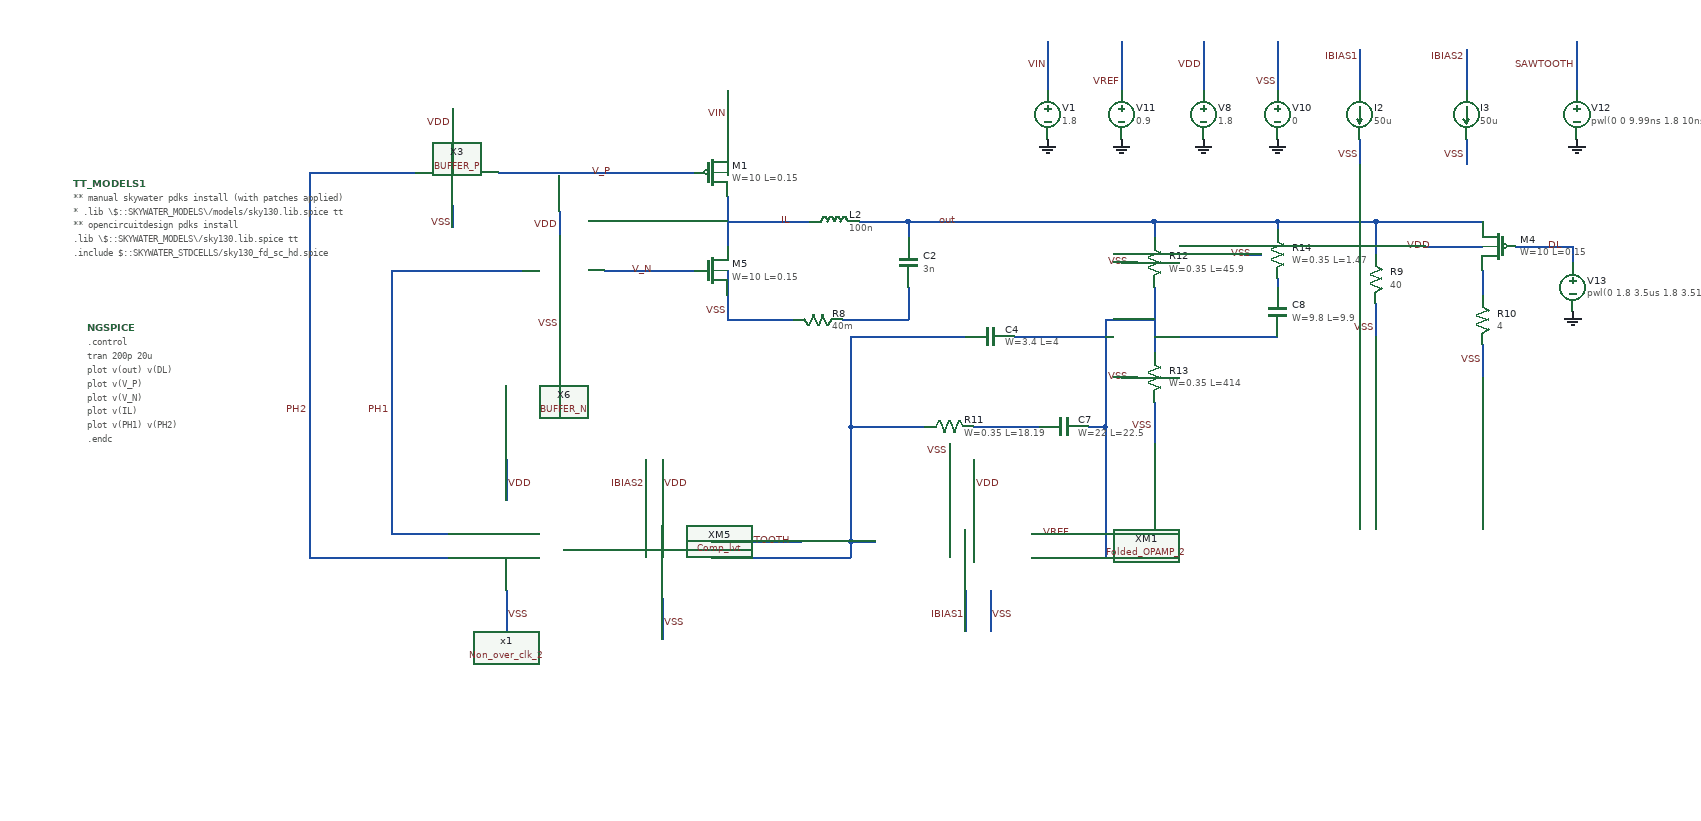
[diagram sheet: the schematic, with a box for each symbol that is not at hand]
v {xschem version=3.0.0 file_version=1.2 }
G {}
K {}
V {}
S {}
E {}
N 1650 880 1650 940 {
lab=IL}
N 1650 820 1650 850 {
lab=VIN}
N 1560 850 1610 850 {
lab=V_P}
N 1650 750 1650 820 {
lab=VIN}
N 1650 1000 1650 1030 {
lab=VSS}
N 1650 910 1710 910 {
lab=IL}
N 1710 910 1750 910 {
lab=IL}
N 1870 910 1870 930 {
lab=out}
N 1810 910 1870 910 {
lab=out}
N 1870 990 1870 1030 {
lab=#net1}
N 1870 910 1980 910 {
lab=out}
N 1950 1200 1950 1250 {
lab=VDD}
N 1970 1360 1970 1410 {
lab=VSS}
N 1940 1360 1940 1410 {
lab=IBIAS1}
N 2020 1320 2070 1320 {
lab=#net2}
N 2020 1290 2070 1290 {
lab=VREF}
N 2230 740 2230 750 {
lab=VDD}
N 2230 690 2230 740 {
lab=VDD}
N 2320 720 2320 740 {
lab=VSS}
N 2320 740 2320 750 {
lab=VSS}
N 2320 690 2320 720 {
lab=VSS}
N 2420 700 2420 760 {
lab=IBIAS1}
N 1570 1200 1570 1250 {
lab=VDD}
N 1570 1370 1570 1420 {
lab=VSS}
N 2130 720 2130 740 {
lab=VREF}
N 2130 740 2130 750 {
lab=VREF}
N 2130 690 2130 720 {
lab=VREF}
N 2070 1320 2100 1320 {
lab=#net2}
N 1550 1200 1550 1250 {
lab=IBIAS2}
N 2685 690 2685 750 {
lab=SAWTOOTH}
N 1370 850 1560 850 {
lab=V_P}
N 1980 910 2160 910 {
lab=out}
N 2170 910 2170 930 {
lab=out}
N 2170 990 2170 1040 {
lab=#net2}
N 2170 1130 2170 1180 {
lab=VSS}
N 1950 1160 2030 1160 {
lab=#net3}
N 1800 1160 1890 1160 {
lab=#net4}
N 1800 1160 1800 1300 {
lab=#net4}
N 2110 1160 2110 1290 {
lab=#net2}
N 2090 1160 2110 1160 {
lab=#net2}
N 1800 1050 1940 1050 {
lab=#net4}
N 2000 1050 2110 1050 {
lab=#net2}
N 2110 1090 2110 1160 {
lab=#net2}
N 1800 1300 1830 1300 {
lab=#net4}
N 2110 1290 2110 1320 {
lab=#net2}
N 2100 1320 2110 1320 {
lab=#net2}
N 2170 910 2320 910 {
lab=out}
N 2320 910 2320 920 {
lab=out}
N 2320 980 2320 990 {
lab=#net5}
N 2160 910 2170 910 {
lab=out}
N 2110 1030 2110 1090 {
lab=#net2}
N 2110 1030 2170 1030 {
lab=#net2}
N 2170 1040 2170 1070 {
lab=#net2}
N 2440 910 2440 950 {
lab=out}
N 2320 910 2440 910 {
lab=out}
N 2440 1010 2440 1050 {
lab=VSS}
N 1630 1320 1800 1320 {
lab=#net4}
N 1800 1300 1800 1320 {
lab=#net4}
N 1560 970 1610 970 {
lab=V_N}
N 1650 970 1650 1000 {
lab=VSS}
N 2440 910 2570 910 {
lab=out}
N 2570 1060 2570 1100 {
lab=VSS}
N 2570 970 2570 1000 {
lab=#net6}
N 2610 940 2680 940 {
lab=DL}
N 2680 940 2680 960 {
lab=DL}
N 1380 1200 1380 1250 {
lab=VDD}
N 1380 1360 1380 1410 {
lab=VSS}
N 1140 850 1270 850 {
lab=PH2}
N 1140 850 1140 1290 {
lab=PH2}
N 1315 890 1315 917.5 {
lab=VSS}
N 1315 772.5 1315 807.5 {
lab=VDD}
N 1500 970 1560 970 {
lab=V_N}
N 1240 970 1400 970 {
lab=PH1}
N 1240 970 1240 1060 {
lab=PH1}
N 1445 1010 1445 1047.5 {
lab=VSS}
N 1445 897.5 1445 927.5 {
lab=VDD}
N 1240 1290 1300 1290 {
lab=PH1}
N 1240 1060 1240 1290 {
lab=PH1}
N 1140 1320 1300 1320 {
lab=PH2}
N 1140 1290 1140 1320 {
lab=PH2}
N 1800 1050 1800 1160 {
lab=#net4}
N 2170 1050 2220 1050 {
lab=#net2}
N 2220 1050 2320 1050 {
lab=#net2}
N 1970 1360 1970 1410 {
lab=VSS}
N 2510 940 2570 940 {
lab=VDD}
N 1630 1300 1740 1300 {
lab=SAWTOOTH}
N 1920 1180 1920 1200 {
lab=VSS}
N 2280 950 2300 950 {
lab=VSS}
N 2130 960 2150 960 {
lab=VSS}
N 2130 1100 2150 1100 {
lab=VSS}
N 1840 1030 1870 1030 {
lab=#net1}
N 1300 1290 1310 1290 {
lab=PH1}
N 1300 1320 1310 1320 {
lab=PH2}
N 1650 1030 1730 1030 {
lab=VSS}
N 1790 1030 1840 1030 {
lab=#net1}
N 1460 1310 1500 1310 {
lab=#net7}
N 2550 700 2550 760 {
lab=IBIAS2}
N 2420 810 2420 830 {
lab=VSS}
N 2550 810 2550 830 {
lab=VSS}
N 2420 830 2420 840 {
lab=VSS}
N 2550 830 2550 840 {
lab=VSS}
N 1450 1310 1460 1310 {
lab=#net7}
N 2070 1290 2080 1290 {
lab=VREF}
N 2500 940 2510 940 {
lab=VDD}
N 2040 740 2040 750 {
lab=VDD}
N 2040 690 2040 740 {
lab=VDD}
C {devices/code.sym} 853 864 0 0 {name=TT_MODELS1
only_toplevel=true
format="tcleval(@value )"
value="** manual skywater pdks install (with patches applied)
* .lib \\\\$::SKYWATER_MODELS\\\\/models/sky130.lib.spice tt

** opencircuitdesign pdks install
.lib \\\\$::SKYWATER_MODELS\\\\/sky130.lib.spice tt
.include $::SKYWATER_STDCELLS/sky130_fd_sc_hd.spice
"
spice_ignore=false}
C {devices/code_shown.sym} 870 1040 0 0 {name=NGSPICE
only_toplevel=true
value="

.control

tran 200p 20u
plot  v(out) v(DL)
plot v(V_P) 
plot v(V_N)
plot v(IL)
plot v(PH1) v(PH2)
.endc
" }
C {sky130_fd_pr/pfet_01v8.sym} 1630 850 0 0 {name=M1
L=0.15
W=10
nf=1
mult=450
ad="'int((nf+1)/2) * W/nf * 0.29'" 
pd="'2*int((nf+1)/2) * (W/nf + 0.29)'"
as="'int((nf+2)/2) * W/nf * 0.29'" 
ps="'2*int((nf+2)/2) * (W/nf + 0.29)'"
nrd="'0.29 / W'" nrs="'0.29 / W'"
sa=0 sb=0 sd=0
model=pfet_01v8
spiceprefix=X
}
C {devices/ind.sym} 1780 910 3 0 {name=L2
m=1
value=100n
footprint=1206
device=inductor}
C {devices/capa.sym} 1870 960 0 0 {name=C2
m=1
value=3n
footprint=1206
device="ceramic capacitor"}
C {devices/lab_wire.sym} 1930 910 0 0 {name=l47 sig_type=std_logic lab=out}
C {devices/lab_wire.sym} 1730 910 0 0 {name=l48 sig_type=std_logic lab=IL}
C {devices/lab_wire.sym} 2420 710 0 0 {name=l52 sig_type=std_logic lab=IBIAS1}
C {devices/isource.sym} 2420 780 0 0 {name=I2 value=50u}
C {devices/vsource.sym} 2230 780 0 0 {name=V8 value=1.8}
C {devices/gnd.sym} 2230 810 0 0 {name=l53 lab=GND}
C {devices/vsource.sym} 2320 780 0 0 {name=V10 value=0}
C {devices/gnd.sym} 2320 810 0 0 {name=l54 lab=GND}
C {devices/lab_wire.sym} 2320 740 0 0 {name=l55 sig_type=std_logic lab=VSS}
C {devices/lab_wire.sym} 1950 1230 0 1 {name=l56 sig_type=std_logic lab=VDD}
C {devices/lab_wire.sym} 1650 1020 0 0 {name=l57 sig_type=std_logic lab=VSS}
C {devices/lab_wire.sym} 1970 1390 0 1 {name=l58 sig_type=std_logic lab=VSS}
C {devices/lab_wire.sym} 1940 1390 0 0 {name=l59 sig_type=std_logic lab=IBIAS1}
C {devices/lab_wire.sym} 1570 1230 0 1 {name=l60 sig_type=std_logic lab=VDD}
C {devices/lab_wire.sym} 1570 1400 0 1 {name=l61 sig_type=std_logic lab=VSS}
C {devices/vsource.sym} 2130 780 0 0 {name=V11 value=0.9}
C {devices/gnd.sym} 2130 810 0 0 {name=l62 lab=GND}
C {devices/lab_wire.sym} 2130 740 0 0 {name=l63 sig_type=std_logic lab=VREF}
C {devices/lab_wire.sym} 1550 1230 0 0 {name=l64 sig_type=std_logic lab=IBIAS2}
C {devices/vsource.sym} 2685 780 0 0 {name=V12 value="pwl(0 0 9.99ns 1.8 10ns 0) r=0"}
C {devices/gnd.sym} 2685 810 0 0 {name=l65 lab=GND}
C {devices/gnd.sym} 2685 810 0 0 {name=l66 lab=GND}
C {devices/lab_wire.sym} 2685 720 0 0 {name=l67 sig_type=std_logic lab=SAWTOOTH}
C {devices/lab_wire.sym} 2170 1160 0 0 {name=l68 sig_type=std_logic lab=VSS}
C {devices/lab_wire.sym} 2070 1290 0 0 {name=l69 sig_type=std_logic lab=VREF}
C {devices/lab_wire.sym} 1730 1300 0 0 {name=l70 sig_type=std_logic lab=SAWTOOTH}
C {devices/lab_wire.sym} 2440 1040 0 0 {name=l71 sig_type=std_logic lab=VSS}
C {sky130_fd_pr/pfet_01v8.sym} 2590 940 0 1 {name=M4
L=0.15
W=10
nf=1
mult=450
ad="'int((nf+1)/2) * W/nf * 0.29'" 
pd="'2*int((nf+1)/2) * (W/nf + 0.29)'"
as="'int((nf+2)/2) * W/nf * 0.29'" 
ps="'2*int((nf+2)/2) * (W/nf + 0.29)'"
nrd="'0.29 / W'" nrs="'0.29 / W'"
sa=0 sb=0 sd=0
model=pfet_01v8
spiceprefix=X
}
C {devices/lab_wire.sym} 2570 1080 0 0 {name=l72 sig_type=std_logic lab=VSS}
C {devices/vsource.sym} 2680 990 0 0 {name=V13 value="pwl(0 1.8 3.5us 1.8 3.51us 0 7us 0) r=0"}
C {devices/gnd.sym} 2680 1020 0 0 {name=l73 lab=GND}
C {devices/gnd.sym} 2680 1020 0 0 {name=l74 lab=GND}
C {devices/lab_wire.sym} 1380 1230 0 1 {name=l75 sig_type=std_logic lab=VDD}
C {devices/lab_wire.sym} 1380 1390 0 1 {name=l76 sig_type=std_logic lab=VSS}
C {DC_DC_Converter/BUFFER/BUFFER_PMOS/BUFFER_P.sym} 1250 900 0 0 {name=X3}
C {devices/lab_wire.sym} 1315 790 0 0 {name=l77 sig_type=std_logic lab=VDD}
C {devices/lab_wire.sym} 1315 912.5 0 0 {name=l78 sig_type=std_logic lab=VSS}
C {devices/lab_wire.sym} 1445 1035 0 0 {name=l79 sig_type=std_logic lab=VSS}
C {devices/lab_wire.sym} 1445 915 0 0 {name=l80 sig_type=std_logic lab=VDD}
C {devices/lab_wire.sym} 1510 850 0 0 {name=l81 sig_type=std_logic lab=V_P}
C {devices/lab_wire.sym} 1560 970 0 0 {name=l82 sig_type=std_logic lab=V_N}
C {devices/lab_wire.sym} 2670 940 0 0 {name=l83 sig_type=std_logic lab=DL}
C {sky130_fd_pr/cap_mim_m3_1.sym} 1970 1050 3 0 {name=C4 model=cap_mim_m3_1 W=3.4 L=4 MF=1 spiceprefix=X}
C {sky130_fd_pr/cap_mim_m3_1.sym} 2060 1160 3 0 {name=C7 model=cap_mim_m3_1 W=22 L=22.5 MF=1 spiceprefix=X}
C {sky130_fd_pr/cap_mim_m3_1.sym} 2320 1020 0 0 {name=C8 model=cap_mim_m3_1 W=9.8 L=9.9 MF=1 spiceprefix=X}
C {devices/lab_wire.sym} 2230 720 0 0 {name=l84 sig_type=std_logic lab=VDD}
C {devices/lab_wire.sym} 2510 940 0 0 {name=l85 sig_type=std_logic lab=VDD}
C {sky130_fd_pr/nfet_01v8.sym} 1630 970 0 0 {name=M5
L=0.15
W=10
nf=1 
mult=150
ad="'int((nf+1)/2) * W/nf * 0.29'" 
pd="'2*int((nf+1)/2) * (W/nf + 0.29)'"
as="'int((nf+2)/2) * W/nf * 0.29'" 
ps="'2*int((nf+2)/2) * (W/nf + 0.29)'"
nrd="'0.29 / W'" nrs="'0.29 / W'"
sa=0 sb=0 sd=0
model=nfet_01v8
spiceprefix=X
}
C {DC_DC_Converter/Comparator/Comp_lvt.sym} 1650 1380 0 1 {name=XM5}
C {devices/lab_wire.sym} 1920 1190 3 0 {name=l86 sig_type=std_logic lab=VSS}
C {devices/lab_wire.sym} 2290 950 0 0 {name=l87 sig_type=std_logic lab=VSS}
C {devices/lab_wire.sym} 2140 960 0 0 {name=l88 sig_type=std_logic lab=VSS}
C {devices/lab_wire.sym} 2140 1100 0 0 {name=l89 sig_type=std_logic lab=VSS}
C {devices/res.sym} 1760 1030 1 0 {name=R8
value=40m
footprint=1206
device=resistor
m=1}
C {devices/res.sym} 2440 980 0 0 {name=R9
value=40
footprint=1206
device=resistor
m=1}
C {devices/res.sym} 2570 1030 0 0 {name=R10
value=4
footprint=1206
device=resistor
m=1}
C {DC_DC_Converter/BUFFER/BUFFER_NMOS/BUFFER_N.sym} 1310 1050 0 0 {name=X6}
C {sky130_fd_pr/res_xhigh_po_0p35.sym} 1920 1160 3 0 {name=R11
W=0.35
L=18.19
model=res_xhigh_po_0p35
spiceprefix=X
mult=1}
C {sky130_fd_pr/res_xhigh_po_0p35.sym} 2170 960 0 0 {name=R12
W=0.35
L=45.9
model=res_xhigh_po_0p35
spiceprefix=X
mult=1}
C {sky130_fd_pr/res_xhigh_po_0p35.sym} 2170 1100 0 0 {name=R13
W=0.35
L=414
model=res_xhigh_po_0p35
spiceprefix=X
mult=1}
C {devices/lab_wire.sym} 2550 710 0 0 {name=l90 sig_type=std_logic lab=IBIAS2}
C {devices/isource.sym} 2550 780 0 0 {name=I3 value=50u}
C {devices/lab_wire.sym} 1240 1140 0 0 {name=l91 sig_type=std_logic lab=PH1}
C {devices/lab_wire.sym} 1140 1140 0 0 {name=l92 sig_type=std_logic lab=PH2}
C {devices/lab_wire.sym} 2550 830 0 0 {name=l93 sig_type=std_logic lab=VSS}
C {devices/lab_wire.sym} 2420 830 0 0 {name=l94 sig_type=std_logic lab=VSS}
C {sky130_fd_pr/res_xhigh_po_0p35.sym} 2320 950 0 0 {name=R14
W=0.35
L=1.47
model=res_xhigh_po_0p35
spiceprefix=X
mult=1}
C {devices/lab_wire.sym} 1650 780 0 0 {name=l1 sig_type=std_logic lab=VIN}
C {DC_DC_Converter/Folded_OPAMP/Folded_OPAMP_2.sym} 2170 1470 0 1 {name=XM1}
C {DC_DC_Converter/Non_Overlap_Clk/Non_over_clk_2.sym} 1580 1570 0 1 {name=x1}
C {devices/vsource.sym} 2040 780 0 0 {name=V1 value=1.8}
C {devices/gnd.sym} 2040 810 0 0 {name=l2 lab=GND}
C {devices/lab_wire.sym} 2040 720 0 0 {name=l3 sig_type=std_logic lab=VIN}
